VERSION 5.7 ;
BUSBITCHARS "[]" ;
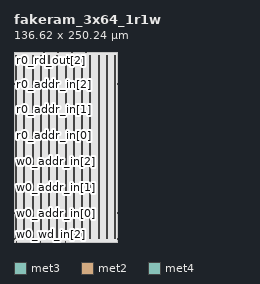
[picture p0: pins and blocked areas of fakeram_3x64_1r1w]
MACRO fakeram_3x64_1r1w
  FOREIGN fakeram_3x64_1r1w 0 0 ;
  SYMMETRY X Y R90 ;
  SIZE 136.620 BY 250.240 ;
  CLASS BLOCK ;
  PIN w0_wd_in[0]
    DIRECTION INPUT ;
    USE SIGNAL ;
    SHAPE ABUTMENT ;
    PORT
      LAYER met3 ;
      RECT 0.000 3.930 0.900 4.230 ;
    END
  END w0_wd_in[0]
  PIN w0_wd_in[1]
    DIRECTION INPUT ;
    USE SIGNAL ;
    SHAPE ABUTMENT ;
    PORT
      LAYER met3 ;
      RECT 135.720 3.930 136.620 4.230 ;
    END
  END w0_wd_in[1]
  PIN w0_wd_in[2]
    DIRECTION OUTPUT ;
    USE SIGNAL ;
    SHAPE ABUTMENT ;
    PORT
      LAYER met2 ;
      RECT 2.690 0.000 2.830 0.420 ;
    END
  END w0_wd_in[2]
  PIN r0_rd_out[0]
    DIRECTION OUTPUT ;
    USE SIGNAL ;
    SHAPE ABUTMENT ;
    PORT
      LAYER met2 ;
      RECT 35.350 0.000 35.490 0.420 ;
    END
  END r0_rd_out[0]
  PIN r0_rd_out[1]
    DIRECTION OUTPUT ;
    USE SIGNAL ;
    SHAPE ABUTMENT ;
    PORT
      LAYER met2 ;
      RECT 68.010 0.000 68.150 0.420 ;
    END
  END r0_rd_out[1]
  PIN r0_rd_out[2]
    DIRECTION OUTPUT ;
    USE SIGNAL ;
    SHAPE ABUTMENT ;
    PORT
      LAYER met2 ;
      RECT 2.690 249.820 2.830 250.240 ;
    END
  END r0_rd_out[2]
  PIN w0_addr_in[0]
    DIRECTION INPUT ;
    USE SIGNAL ;
    SHAPE ABUTMENT ;
    PORT
      LAYER met3 ;
      RECT 0.000 37.930 0.900 38.230 ;
    END
  END w0_addr_in[0]
  PIN w0_addr_in[1]
    DIRECTION INPUT ;
    USE SIGNAL ;
    SHAPE ABUTMENT ;
    PORT
      LAYER met3 ;
      RECT 0.000 71.930 0.900 72.230 ;
    END
  END w0_addr_in[1]
  PIN w0_addr_in[2]
    DIRECTION INPUT ;
    USE SIGNAL ;
    SHAPE ABUTMENT ;
    PORT
      LAYER met3 ;
      RECT 0.000 105.930 0.900 106.230 ;
    END
  END w0_addr_in[2]
  PIN w0_addr_in[3]
    DIRECTION INPUT ;
    USE SIGNAL ;
    SHAPE ABUTMENT ;
    PORT
      LAYER met3 ;
      RECT 135.720 37.930 136.620 38.230 ;
    END
  END w0_addr_in[3]
  PIN w0_addr_in[4]
    DIRECTION INPUT ;
    USE SIGNAL ;
    SHAPE ABUTMENT ;
    PORT
      LAYER met3 ;
      RECT 135.720 71.930 136.620 72.230 ;
    END
  END w0_addr_in[4]
  PIN w0_addr_in[5]
    DIRECTION INPUT ;
    USE SIGNAL ;
    SHAPE ABUTMENT ;
    PORT
      LAYER met3 ;
      RECT 135.720 105.930 136.620 106.230 ;
    END
  END w0_addr_in[5]
  PIN r0_addr_in[0]
    DIRECTION INPUT ;
    USE SIGNAL ;
    SHAPE ABUTMENT ;
    PORT
      LAYER met3 ;
      RECT 0.000 139.930 0.900 140.230 ;
    END
  END r0_addr_in[0]
  PIN r0_addr_in[1]
    DIRECTION INPUT ;
    USE SIGNAL ;
    SHAPE ABUTMENT ;
    PORT
      LAYER met3 ;
      RECT 0.000 173.930 0.900 174.230 ;
    END
  END r0_addr_in[1]
  PIN r0_addr_in[2]
    DIRECTION INPUT ;
    USE SIGNAL ;
    SHAPE ABUTMENT ;
    PORT
      LAYER met3 ;
      RECT 0.000 207.930 0.900 208.230 ;
    END
  END r0_addr_in[2]
  PIN r0_addr_in[3]
    DIRECTION INPUT ;
    USE SIGNAL ;
    SHAPE ABUTMENT ;
    PORT
      LAYER met3 ;
      RECT 135.720 139.930 136.620 140.230 ;
    END
  END r0_addr_in[3]
  PIN r0_addr_in[4]
    DIRECTION INPUT ;
    USE SIGNAL ;
    SHAPE ABUTMENT ;
    PORT
      LAYER met3 ;
      RECT 135.720 173.930 136.620 174.230 ;
    END
  END r0_addr_in[4]
  PIN r0_addr_in[5]
    DIRECTION INPUT ;
    USE SIGNAL ;
    SHAPE ABUTMENT ;
    PORT
      LAYER met3 ;
      RECT 135.720 207.930 136.620 208.230 ;
    END
  END r0_addr_in[5]
  PIN w0_we_in
    DIRECTION INPUT ;
    USE SIGNAL ;
    SHAPE ABUTMENT ;
    PORT
      LAYER met2 ;
      RECT 21.090 249.820 21.230 250.240 ;
    END
  END w0_we_in
  PIN w0_ce_in
    DIRECTION INPUT ;
    USE SIGNAL ;
    SHAPE ABUTMENT ;
    PORT
      LAYER met2 ;
      RECT 39.490 249.820 39.630 250.240 ;
    END
  END w0_ce_in
  PIN w0_clk
    DIRECTION INPUT ;
    USE SIGNAL ;
    SHAPE ABUTMENT ;
    PORT
      LAYER met2 ;
      RECT 57.890 249.820 58.030 250.240 ;
    END
  END w0_clk
  PIN r0_ce_in
    DIRECTION INPUT ;
    USE SIGNAL ;
    SHAPE ABUTMENT ;
    PORT
      LAYER met2 ;
      RECT 76.290 249.820 76.430 250.240 ;
    END
  END r0_ce_in
  PIN r0_clk
    DIRECTION INPUT ;
    USE SIGNAL ;
    SHAPE ABUTMENT ;
    PORT
      LAYER met2 ;
      RECT 94.690 249.820 94.830 250.240 ;
    END
  END r0_clk
  PIN VSS
    DIRECTION INOUT ;
    USE GROUND ;
    PORT
      LAYER met4 ;
      RECT 2.160 4.080 3.360 246.160 ;
      RECT 13.040 4.080 14.240 246.160 ;
      RECT 23.920 4.080 25.120 246.160 ;
      RECT 34.800 4.080 36.000 246.160 ;
      RECT 45.680 4.080 46.880 246.160 ;
      RECT 56.560 4.080 57.760 246.160 ;
      RECT 67.440 4.080 68.640 246.160 ;
      RECT 78.320 4.080 79.520 246.160 ;
      RECT 89.200 4.080 90.400 246.160 ;
      RECT 100.080 4.080 101.280 246.160 ;
      RECT 110.960 4.080 112.160 246.160 ;
      RECT 121.840 4.080 123.040 246.160 ;
      RECT 132.720 4.080 133.920 246.160 ;
    END
  END VSS
  PIN VDD
    DIRECTION INOUT ;
    USE POWER ;
    PORT
      LAYER met4 ;
      RECT 2.160 4.080 3.360 246.160 ;
      RECT 13.040 4.080 14.240 246.160 ;
      RECT 23.920 4.080 25.120 246.160 ;
      RECT 34.800 4.080 36.000 246.160 ;
      RECT 45.680 4.080 46.880 246.160 ;
      RECT 56.560 4.080 57.760 246.160 ;
      RECT 67.440 4.080 68.640 246.160 ;
      RECT 78.320 4.080 79.520 246.160 ;
      RECT 89.200 4.080 90.400 246.160 ;
      RECT 100.080 4.080 101.280 246.160 ;
      RECT 110.960 4.080 112.160 246.160 ;
      RECT 121.840 4.080 123.040 246.160 ;
      RECT 132.720 4.080 133.920 246.160 ;
    END
  END VDD
  OBS
    LAYER met1 ;
    RECT 0 0 136.620 250.240 ;
    LAYER met2 ;
    RECT 0 0 136.620 250.240 ;
    LAYER met3 ;
    RECT 0 0 136.620 250.240 ;
    LAYER met4 ;
    RECT 0 0 136.620 250.240 ;
  END
END fakeram_3x64_1r1w

END LIBRARY
